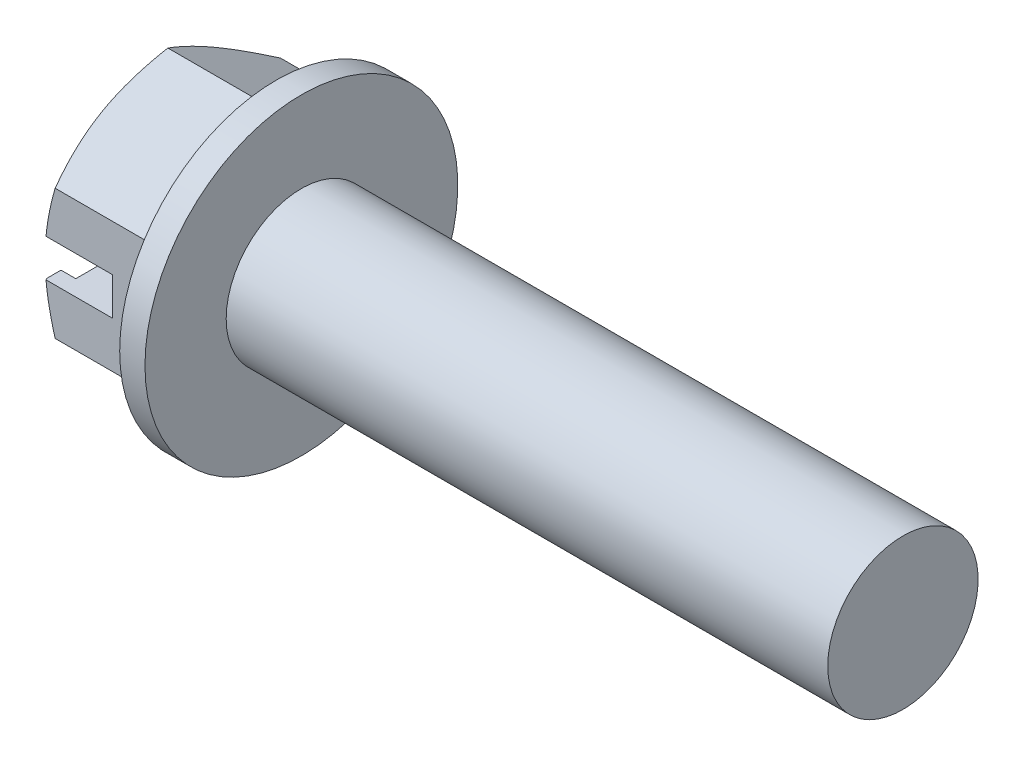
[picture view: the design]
ISO-10303-21;
HEADER;
FILE_DESCRIPTION(('STEP AP214'),'2;1');
FILE_NAME('part.step','',(''),(''),'','','');
FILE_SCHEMA(('AUTOMOTIVE_DESIGN { 1 0 10303 214 1 1 1 1 }'));
ENDSEC;
DATA;
#1=APPLICATION_CONTEXT('core data for automotive mechanical design processes');
#2=APPLICATION_PROTOCOL_DEFINITION('international standard','automotive_design',2000,#1);
#3=PRODUCT_CONTEXT('',#1,'mechanical');
#4=PRODUCT('Part','Part','',(#3));
#5=PRODUCT_RELATED_PRODUCT_CATEGORY('part','',(#4));
#6=PRODUCT_DEFINITION_FORMATION('','',#4);
#7=PRODUCT_DEFINITION_CONTEXT('part definition',#1,'design');
#8=PRODUCT_DEFINITION('design','',#6,#7);
#9=PRODUCT_DEFINITION_SHAPE('','',#8);
#10=(LENGTH_UNIT() NAMED_UNIT(*) SI_UNIT(.MILLI.,.METRE.));
#11=(NAMED_UNIT(*) PLANE_ANGLE_UNIT() SI_UNIT($,.RADIAN.));
#12=(NAMED_UNIT(*) SI_UNIT($,.STERADIAN.) SOLID_ANGLE_UNIT());
#13=UNCERTAINTY_MEASURE_WITH_UNIT(LENGTH_MEASURE(1.E-05),#10,'distance_accuracy_value','');
#14=(GEOMETRIC_REPRESENTATION_CONTEXT(3) GLOBAL_UNCERTAINTY_ASSIGNED_CONTEXT((#13)) GLOBAL_UNIT_ASSIGNED_CONTEXT((#10,
#11,#12)) REPRESENTATION_CONTEXT('',''));
#15=CARTESIAN_POINT('',(0.,0.,0.));
#16=DIRECTION('',(0.,0.,1.));
#17=DIRECTION('',(1.,0.,0.));
#18=AXIS2_PLACEMENT_3D('',#15,#16,#17);
#19=CARTESIAN_POINT('',(0.,0.,0.));
#20=DIRECTION('',(-1.,0.,0.));
#21=DIRECTION('',(0.,0.,1.));
#22=AXIS2_PLACEMENT_3D('',#19,#20,#21);
#23=PLANE('',#22);
#24=DIRECTION('',(0.,0.,-1.));
#25=VECTOR('',#24,1.);
#26=CARTESIAN_POINT('',(0.,-1.1938,0.));
#27=LINE('',#26,#25);
#28=CARTESIAN_POINT('',(0.,-1.1938,7.03685443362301));
#29=VERTEX_POINT('',#28);
#30=CARTESIAN_POINT('',(0.,-1.1938,6.13006336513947));
#31=VERTEX_POINT('',#30);
#32=EDGE_CURVE('E179',#29,#31,#27,.T.);
#33=ORIENTED_EDGE('',*,*,#32,.T.);
#34=CARTESIAN_POINT('',(0.,0.,0.));
#35=DIRECTION('',(1.,0.,0.));
#36=DIRECTION('',(0.,0.,-1.));
#37=AXIS2_PLACEMENT_3D('',#34,#35,#36);
#38=CIRCLE('',#37,6.245225);
#39=CARTESIAN_POINT('',(0.,-1.1938,-6.13006336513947));
#40=VERTEX_POINT('',#39);
#41=EDGE_CURVE('E164',#31,#40,#38,.T.);
#42=ORIENTED_EDGE('',*,*,#41,.T.);
#43=CARTESIAN_POINT('',(0.,-1.1938,-7.03685443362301));
#44=VERTEX_POINT('',#43);
#45=EDGE_CURVE('E176',#40,#44,#27,.T.);
#46=ORIENTED_EDGE('',*,*,#45,.T.);
#47=CARTESIAN_POINT('',(0.,0.,0.));
#48=DIRECTION('',(-1.,0.,0.));
#49=DIRECTION('',(0.,0.,1.));
#50=AXIS2_PLACEMENT_3D('',#47,#48,#49);
#51=CIRCLE('',#50,7.13739999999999);
#52=CARTESIAN_POINT('',(0.,-6.18116973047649,-3.5687000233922));
#53=VERTEX_POINT('',#52);
#54=EDGE_CURVE('E204',#44,#53,#51,.T.);
#55=ORIENTED_EDGE('',*,*,#54,.T.);
#56=CARTESIAN_POINT('',(0.,-6.18116973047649,3.5687000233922));
#57=VERTEX_POINT('',#56);
#58=EDGE_CURVE('E226',#53,#57,#51,.T.);
#59=ORIENTED_EDGE('',*,*,#58,.T.);
#60=EDGE_CURVE('E203',#57,#29,#51,.T.);
#61=ORIENTED_EDGE('',*,*,#60,.T.);
#62=EDGE_LOOP('',(#33,#42,#46,#55,#59,#61));
#63=FACE_BOUND('',#62,.T.);
#64=ADVANCED_FACE('F33',(#63),#23,.T.);
#65=DIRECTION('',(0.,0.,1.));
#66=VECTOR('',#65,1.);
#67=CARTESIAN_POINT('',(0.,1.1938,0.));
#68=LINE('',#67,#66);
#69=CARTESIAN_POINT('',(0.,1.1938,-7.03685443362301));
#70=VERTEX_POINT('',#69);
#71=CARTESIAN_POINT('',(0.,1.1938,-6.13006336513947));
#72=VERTEX_POINT('',#71);
#73=EDGE_CURVE('E168',#70,#72,#68,.T.);
#74=ORIENTED_EDGE('',*,*,#73,.T.);
#75=CARTESIAN_POINT('',(0.,1.1938,6.13006336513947));
#76=VERTEX_POINT('',#75);
#77=EDGE_CURVE('E157',#72,#76,#38,.T.);
#78=ORIENTED_EDGE('',*,*,#77,.T.);
#79=CARTESIAN_POINT('',(0.,1.1938,7.03685443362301));
#80=VERTEX_POINT('',#79);
#81=EDGE_CURVE('E177',#76,#80,#68,.T.);
#82=ORIENTED_EDGE('',*,*,#81,.T.);
#83=CARTESIAN_POINT('',(0.,6.18116973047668,3.56870002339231));
#84=VERTEX_POINT('',#83);
#85=EDGE_CURVE('E195',#80,#84,#51,.T.);
#86=ORIENTED_EDGE('',*,*,#85,.T.);
#87=CARTESIAN_POINT('',(0.,6.18116973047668,-3.56870002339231));
#88=VERTEX_POINT('',#87);
#89=EDGE_CURVE('E198',#84,#88,#51,.T.);
#90=ORIENTED_EDGE('',*,*,#89,.T.);
#91=EDGE_CURVE('E175',#88,#70,#51,.T.);
#92=ORIENTED_EDGE('',*,*,#91,.T.);
#93=EDGE_LOOP('',(#74,#78,#82,#86,#90,#92));
#94=FACE_BOUND('',#93,.T.);
#95=ADVANCED_FACE('F172',(#94),#23,.T.);
#96=CARTESIAN_POINT('',(4.2672,-1.1938,-8.24180138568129));
#97=DIRECTION('',(0.,1.,0.));
#98=DIRECTION('',(0.,0.,1.));
#99=AXIS2_PLACEMENT_3D('',#96,#97,#98);
#100=PLANE('',#99);
#101=ORIENTED_EDGE('',*,*,#45,.F.);
#102=DIRECTION('',(-1.,0.,0.));
#103=VECTOR('',#102,1.);
#104=CARTESIAN_POINT('',(0.936625,-1.1938,-6.13006336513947));
#105=LINE('',#104,#103);
#106=CARTESIAN_POINT('',(0.936625,-1.1938,-6.13006336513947));
#107=VERTEX_POINT('',#106);
#108=EDGE_CURVE('E338',#40,#107,#105,.F.);
#109=ORIENTED_EDGE('',*,*,#108,.T.);
#110=DIRECTION('',(0.,0.,-1.));
#111=VECTOR('',#110,1.);
#112=CARTESIAN_POINT('',(0.936625,-1.1938,-8.24180138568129));
#113=LINE('',#112,#111);
#114=CARTESIAN_POINT('',(0.936625,-1.1938,6.13006336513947));
#115=VERTEX_POINT('',#114);
#116=EDGE_CURVE('E189',#115,#107,#113,.T.);
#117=ORIENTED_EDGE('',*,*,#116,.F.);
#118=DIRECTION('',(-1.,0.,0.));
#119=VECTOR('',#118,1.);
#120=CARTESIAN_POINT('',(0.936625,-1.1938,6.13006336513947));
#121=LINE('',#120,#119);
#122=EDGE_CURVE('E287',#115,#31,#121,.T.);
#123=ORIENTED_EDGE('',*,*,#122,.T.);
#124=ORIENTED_EDGE('',*,*,#32,.F.);
#125=CARTESIAN_POINT('',(3.26043260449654,-1.1938,12.7287757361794));
#126=CARTESIAN_POINT('',(2.98204474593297,-1.1938,12.2444551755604));
#127=CARTESIAN_POINT('',(2.70374242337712,-1.1938,11.7600853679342));
#128=CARTESIAN_POINT('',(2.14746424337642,-1.1938,10.79121068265));
#129=CARTESIAN_POINT('',(1.8694883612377,-1.1938,10.3067058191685));
#130=CARTESIAN_POINT('',(1.31403888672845,-1.1938,9.33756042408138));
#131=CARTESIAN_POINT('',(1.03656519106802,-1.1938,8.85291995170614));
#132=CARTESIAN_POINT('',(0.620878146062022,-1.1938,8.12563576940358));
#133=CARTESIAN_POINT('',(0.482397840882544,-1.1938,7.88314465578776));
#134=CARTESIAN_POINT('',(0.205671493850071,-1.1938,7.39802631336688));
#135=CARTESIAN_POINT('',(0.0674254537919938,-1.1938,7.1553990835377));
#136=CARTESIAN_POINT('',(-0.208818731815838,-1.1938,6.66984777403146));
#137=CARTESIAN_POINT('',(-0.346816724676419,-1.1938,6.42692360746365));
#138=CARTESIAN_POINT('',(-0.62237324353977,-1.1938,5.94083477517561));
#139=CARTESIAN_POINT('',(-0.759931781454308,-1.1938,5.69767011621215));
#140=CARTESIAN_POINT('',(-1.03438897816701,-1.1938,5.21104351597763));
#141=CARTESIAN_POINT('',(-1.17128778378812,-1.1938,4.96758165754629));
#142=CARTESIAN_POINT('',(-1.4441587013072,-1.1938,4.48010659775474));
#143=CARTESIAN_POINT('',(-1.58013072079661,-1.1938,4.23609334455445));
#144=CARTESIAN_POINT('',(-1.7829941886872,-1.1938,3.86933760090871));
#145=CARTESIAN_POINT('',(-1.85046016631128,-1.1938,3.74691304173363));
#146=CARTESIAN_POINT('',(-1.98488099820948,-1.1938,3.50178681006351));
#147=CARTESIAN_POINT('',(-2.05183586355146,-1.1938,3.37908514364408));
#148=CARTESIAN_POINT('',(-2.18504184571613,-1.1938,3.13334895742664));
#149=CARTESIAN_POINT('',(-2.25129317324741,-1.1938,3.01031455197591));
#150=CARTESIAN_POINT('',(-2.38285615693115,-1.1938,2.7637302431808));
#151=CARTESIAN_POINT('',(-2.44816773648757,-1.1938,2.64018029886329));
#152=CARTESIAN_POINT('',(-2.57750557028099,-1.1938,2.39222873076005));
#153=CARTESIAN_POINT('',(-2.64153027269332,-1.1938,2.26782629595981));
#154=CARTESIAN_POINT('',(-2.76753475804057,-1.1938,2.01801587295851));
#155=CARTESIAN_POINT('',(-2.82951499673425,-1.1938,1.89260811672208));
#156=CARTESIAN_POINT('',(-2.92008574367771,-1.1938,1.7032539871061));
#157=CARTESIAN_POINT('',(-2.94989305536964,-1.1938,1.63989083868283));
#158=CARTESIAN_POINT('',(-3.0084424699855,-1.1938,1.51268002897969));
#159=CARTESIAN_POINT('',(-3.03718466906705,-1.1938,1.44883241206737));
#160=CARTESIAN_POINT('',(-3.09331464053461,-1.1938,1.32048035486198));
#161=CARTESIAN_POINT('',(-3.12070135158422,-1.1938,1.25597544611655));
#162=CARTESIAN_POINT('',(-3.17361063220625,-1.1938,1.126184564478));
#163=CARTESIAN_POINT('',(-3.19913261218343,-1.1938,1.06089835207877));
#164=CARTESIAN_POINT('',(-3.223470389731,-1.1938,0.995155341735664));
#165=B_SPLINE_CURVE_WITH_KNOTS('',3,(#125,#126,#127,#128,#129,#130,#131,#132,#133,#134,#135,
#136,#137,#138,#139,#140,#141,#142,#143,#144,#145,#146,#147,#148,#149,#150,#151,#152,#153,#154,
#155,#156,#157,#158,#159,#160,#161,#162,#163,#164),.UNSPECIFIED.,.F.,.F.,(4,2,2,2,2,2,2,2,2,2,2,
2,2,2,2,2,2,2,2,4),(0.,1.67588667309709,3.35163714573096,5.02699109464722,5.86473118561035,
6.70247766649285,7.54063032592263,8.3787600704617,9.21669377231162,10.0547098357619,
10.4740595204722,10.8934000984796,11.3126113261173,11.7318565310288,12.1515801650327,
12.5712095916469,12.7812741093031,12.9913196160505,13.2015270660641,13.4118006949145),.UNSPECIFIED.);
#166=CARTESIAN_POINT('',(0.0572435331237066,-1.1938,7.1374));
#167=VERTEX_POINT('',#166);
#168=EDGE_CURVE('E284',#167,#29,#165,.T.);
#169=ORIENTED_EDGE('',*,*,#168,.F.);
#170=DIRECTION('',(-1.,0.,0.));
#171=VECTOR('',#170,1.);
#172=CARTESIAN_POINT('',(7.493,-1.1938,7.1374));
#173=LINE('',#172,#171);
#174=CARTESIAN_POINT('',(4.2672,-1.1938,7.1374));
#175=VERTEX_POINT('',#174);
#176=EDGE_CURVE('E290',#175,#167,#173,.T.);
#177=ORIENTED_EDGE('',*,*,#176,.F.);
#178=DIRECTION('',(0.,0.,-1.));
#179=VECTOR('',#178,1.);
#180=CARTESIAN_POINT('',(4.2672,-1.1938,-8.24180138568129));
#181=LINE('',#180,#179);
#182=CARTESIAN_POINT('',(4.2672,-1.1938,-7.1374));
#183=VERTEX_POINT('',#182);
#184=EDGE_CURVE('E335',#175,#183,#181,.T.);
#185=ORIENTED_EDGE('',*,*,#184,.T.);
#186=DIRECTION('',(1.,0.,0.));
#187=VECTOR('',#186,1.);
#188=CARTESIAN_POINT('',(7.493,-1.1938,-7.1374));
#189=LINE('',#188,#187);
#190=CARTESIAN_POINT('',(0.0572435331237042,-1.1938,-7.1374));
#191=VERTEX_POINT('',#190);
#192=EDGE_CURVE('E291',#191,#183,#189,.T.);
#193=ORIENTED_EDGE('',*,*,#192,.F.);
#194=CARTESIAN_POINT('',(-3.223470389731,-1.1938,-0.995155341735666));
#195=CARTESIAN_POINT('',(-3.19924138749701,-1.1938,-1.0606056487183));
#196=CARTESIAN_POINT('',(-3.17383818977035,-1.1938,-1.1256031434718));
#197=CARTESIAN_POINT('',(-3.12118075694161,-1.1938,-1.25482287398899));
#198=CARTESIAN_POINT('',(-3.09392710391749,-1.1938,-1.31904534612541));
#199=CARTESIAN_POINT('',(-3.03807357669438,-1.1938,-1.44683300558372));
#200=CARTESIAN_POINT('',(-3.00947484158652,-1.1938,-1.51039869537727));
#201=CARTESIAN_POINT('',(-2.95121813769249,-1.1938,-1.63704855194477));
#202=CARTESIAN_POINT('',(-2.9215600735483,-1.1938,-1.7001326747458));
#203=CARTESIAN_POINT('',(-2.83143708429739,-1.1938,-1.88866522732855));
#204=CARTESIAN_POINT('',(-2.76976096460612,-1.1938,-2.01353350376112));
#205=CARTESIAN_POINT('',(-2.64436453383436,-1.1938,-2.26227255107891));
#206=CARTESIAN_POINT('',(-2.58064367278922,-1.1938,-2.38614304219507));
#207=CARTESIAN_POINT('',(-2.41929157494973,-1.1938,-2.69563915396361));
#208=CARTESIAN_POINT('',(-2.32080635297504,-1.1938,-2.88081872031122));
#209=CARTESIAN_POINT('',(-2.12205686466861,-1.1938,-3.25022110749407));
#210=CARTESIAN_POINT('',(-2.02179255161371,-1.1938,-3.43444390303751));
#211=CARTESIAN_POINT('',(-1.82013033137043,-1.1938,-3.80225262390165));
#212=CARTESIAN_POINT('',(-1.71873249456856,-1.1938,-3.98583858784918));
#213=CARTESIAN_POINT('',(-1.51516860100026,-1.1938,-4.35258440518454));
#214=CARTESIAN_POINT('',(-1.41300254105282,-1.1938,-4.53574425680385));
#215=CARTESIAN_POINT('',(-1.10543651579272,-1.1938,-5.0852656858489));
#216=CARTESIAN_POINT('',(-0.899238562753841,-1.1938,-5.45118036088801));
#217=CARTESIAN_POINT('',(-0.485698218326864,-1.1938,-6.18235721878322));
#218=CARTESIAN_POINT('',(-0.27835583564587,-1.1938,-6.54761940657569));
#219=CARTESIAN_POINT('',(0.205814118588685,-1.1938,-7.39864831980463));
#220=CARTESIAN_POINT('',(0.482912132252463,-1.1938,-7.88426115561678));
#221=CARTESIAN_POINT('',(1.03780984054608,-1.1938,-8.85508746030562));
#222=CARTESIAN_POINT('',(1.31560953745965,-1.1938,-9.34030092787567));
#223=CARTESIAN_POINT('',(1.87108240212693,-1.1938,-10.3094870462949));
#224=CARTESIAN_POINT('',(2.14875467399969,-1.1938,-10.7934602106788));
#225=CARTESIAN_POINT('',(2.70440087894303,-1.1938,-11.7612302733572));
#226=CARTESIAN_POINT('',(2.98237481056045,-1.1938,-12.2450271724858));
#227=CARTESIAN_POINT('',(3.26043260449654,-1.1938,-12.7287757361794));
#228=B_SPLINE_CURVE_WITH_KNOTS('',3,(#194,#195,#196,#197,#198,#199,#200,#201,#202,#203,#204,
#205,#206,#207,#208,#209,#210,#211,#212,#213,#214,#215,#216,#217,#218,#219,#220,#221,#222,#223,
#224,#225,#226,#227),.UNSPECIFIED.,.F.,.F.,(4,2,2,2,2,2,2,2,2,2,2,2,2,2,2,2,4),(0.,
0.209337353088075,0.418609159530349,0.627706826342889,0.836823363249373,1.2545977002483,
1.6724853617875,2.30168509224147,2.93090137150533,3.560078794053,4.1892588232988,
5.44929382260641,6.70931924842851,8.3866456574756,10.0639775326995,11.7378911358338,
13.4117967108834),.UNSPECIFIED.);
#229=EDGE_CURVE('E296',#44,#191,#228,.T.);
#230=ORIENTED_EDGE('',*,*,#229,.F.);
#231=EDGE_LOOP('',(#101,#109,#117,#123,#124,#169,#177,#185,#193,#230));
#232=FACE_BOUND('',#231,.T.);
#233=ADVANCED_FACE('F278',(#232),#100,.T.);
#234=CARTESIAN_POINT('',(4.2672,1.1938,8.24180138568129));
#235=DIRECTION('',(0.,-1.,0.));
#236=DIRECTION('',(0.,0.,-1.));
#237=AXIS2_PLACEMENT_3D('',#234,#235,#236);
#238=PLANE('',#237);
#239=ORIENTED_EDGE('',*,*,#81,.F.);
#240=DIRECTION('',(-1.,0.,0.));
#241=VECTOR('',#240,1.);
#242=CARTESIAN_POINT('',(0.936625,1.1938,6.13006336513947));
#243=LINE('',#242,#241);
#244=CARTESIAN_POINT('',(0.936625,1.1938,6.13006336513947));
#245=VERTEX_POINT('',#244);
#246=EDGE_CURVE('E11',#76,#245,#243,.F.);
#247=ORIENTED_EDGE('',*,*,#246,.T.);
#248=DIRECTION('',(0.,0.,1.));
#249=VECTOR('',#248,1.);
#250=CARTESIAN_POINT('',(0.936625,1.1938,8.24180138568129));
#251=LINE('',#250,#249);
#252=CARTESIAN_POINT('',(0.936625,1.1938,-6.13006336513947));
#253=VERTEX_POINT('',#252);
#254=EDGE_CURVE('E170',#253,#245,#251,.T.);
#255=ORIENTED_EDGE('',*,*,#254,.F.);
#256=DIRECTION('',(-1.,0.,0.));
#257=VECTOR('',#256,1.);
#258=CARTESIAN_POINT('',(0.936625,1.1938,-6.13006336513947));
#259=LINE('',#258,#257);
#260=EDGE_CURVE('E41',#253,#72,#259,.T.);
#261=ORIENTED_EDGE('',*,*,#260,.T.);
#262=ORIENTED_EDGE('',*,*,#73,.F.);
#263=CARTESIAN_POINT('',(3.26043260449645,1.1938,-12.7287757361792));
#264=CARTESIAN_POINT('',(2.98204474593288,1.1938,-12.2444551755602));
#265=CARTESIAN_POINT('',(2.70374242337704,1.1938,-11.760085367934));
#266=CARTESIAN_POINT('',(2.14746424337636,1.1938,-10.7912106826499));
#267=CARTESIAN_POINT('',(1.86948836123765,1.1938,-10.3067058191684));
#268=CARTESIAN_POINT('',(1.31403888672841,1.1938,-9.33756042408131));
#269=CARTESIAN_POINT('',(1.03656519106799,1.1938,-8.85291995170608));
#270=CARTESIAN_POINT('',(0.620878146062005,1.1938,-8.12563576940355));
#271=CARTESIAN_POINT('',(0.482397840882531,1.1938,-7.88314465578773));
#272=CARTESIAN_POINT('',(0.205671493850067,1.1938,-7.39802631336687));
#273=CARTESIAN_POINT('',(0.0674254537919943,1.1938,-7.1553990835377));
#274=CARTESIAN_POINT('',(-0.208818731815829,1.1938,-6.66984777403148));
#275=CARTESIAN_POINT('',(-0.346816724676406,1.1938,-6.42692360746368));
#276=CARTESIAN_POINT('',(-0.622373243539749,1.1938,-5.94083477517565));
#277=CARTESIAN_POINT('',(-0.759931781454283,1.1938,-5.69767011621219));
#278=CARTESIAN_POINT('',(-1.03438897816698,1.1938,-5.21104351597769));
#279=CARTESIAN_POINT('',(-1.17128778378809,1.1938,-4.96758165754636));
#280=CARTESIAN_POINT('',(-1.44415870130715,1.1938,-4.48010659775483));
#281=CARTESIAN_POINT('',(-1.58013072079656,1.1938,-4.23609334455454));
#282=CARTESIAN_POINT('',(-1.78299418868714,1.1938,-3.86933760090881));
#283=CARTESIAN_POINT('',(-1.85046016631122,1.1938,-3.74691304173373));
#284=CARTESIAN_POINT('',(-1.98488099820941,1.1938,-3.50178681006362));
#285=CARTESIAN_POINT('',(-2.05183586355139,1.1938,-3.37908514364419));
#286=CARTESIAN_POINT('',(-2.18504184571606,1.1938,-3.13334895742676));
#287=CARTESIAN_POINT('',(-2.25129317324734,1.1938,-3.01031455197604));
#288=CARTESIAN_POINT('',(-2.38285615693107,1.1938,-2.76373024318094));
#289=CARTESIAN_POINT('',(-2.4481677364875,1.1938,-2.64018029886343));
#290=CARTESIAN_POINT('',(-2.57750557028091,1.1938,-2.3922287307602));
#291=CARTESIAN_POINT('',(-2.64153027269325,1.1938,-2.26782629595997));
#292=CARTESIAN_POINT('',(-2.76753475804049,1.1938,-2.01801587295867));
#293=CARTESIAN_POINT('',(-2.82951499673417,1.1938,-1.89260811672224));
#294=CARTESIAN_POINT('',(-2.92008574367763,1.1938,-1.70325398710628));
#295=CARTESIAN_POINT('',(-2.94989305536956,1.1938,-1.639890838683));
#296=CARTESIAN_POINT('',(-3.00844246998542,1.1938,-1.51268002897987));
#297=CARTESIAN_POINT('',(-3.03718466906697,1.1938,-1.44883241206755));
#298=CARTESIAN_POINT('',(-3.09331464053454,1.1938,-1.32048035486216));
#299=CARTESIAN_POINT('',(-3.12070135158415,1.1938,-1.25597544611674));
#300=CARTESIAN_POINT('',(-3.17361063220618,1.1938,-1.12618456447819));
#301=CARTESIAN_POINT('',(-3.19913261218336,1.1938,-1.06089835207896));
#302=CARTESIAN_POINT('',(-3.22347038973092,1.1938,-0.995155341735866));
#303=B_SPLINE_CURVE_WITH_KNOTS('',3,(#263,#264,#265,#266,#267,#268,#269,#270,#271,#272,#273,
#274,#275,#276,#277,#278,#279,#280,#281,#282,#283,#284,#285,#286,#287,#288,#289,#290,#291,#292,
#293,#294,#295,#296,#297,#298,#299,#300,#301,#302),.UNSPECIFIED.,.F.,.F.,(4,2,2,2,2,2,2,2,2,2,2,
2,2,2,2,2,2,2,2,4),(0.,1.67588667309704,3.35163714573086,5.02699109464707,5.86473118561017,
6.70247766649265,7.5406303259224,8.37876007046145,9.21669377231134,10.0547098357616,
10.4740595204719,10.8934000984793,11.3126113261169,11.7318565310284,12.1515801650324,
12.5712095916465,12.7812741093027,12.9913196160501,13.2015270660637,13.4118006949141),.UNSPECIFIED.);
#304=CARTESIAN_POINT('',(0.0572435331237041,1.1938,-7.1374));
#305=VERTEX_POINT('',#304);
#306=EDGE_CURVE('E320',#305,#70,#303,.T.);
#307=ORIENTED_EDGE('',*,*,#306,.F.);
#308=DIRECTION('',(-1.,0.,0.));
#309=VECTOR('',#308,1.);
#310=CARTESIAN_POINT('',(7.493,1.1938,-7.1374));
#311=LINE('',#310,#309);
#312=CARTESIAN_POINT('',(4.2672,1.1938,-7.1374));
#313=VERTEX_POINT('',#312);
#314=EDGE_CURVE('E317',#313,#305,#311,.T.);
#315=ORIENTED_EDGE('',*,*,#314,.F.);
#316=DIRECTION('',(0.,0.,1.));
#317=VECTOR('',#316,1.);
#318=CARTESIAN_POINT('',(4.2672,1.1938,8.24180138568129));
#319=LINE('',#318,#317);
#320=CARTESIAN_POINT('',(4.2672,1.1938,7.1374));
#321=VERTEX_POINT('',#320);
#322=EDGE_CURVE('E332',#313,#321,#319,.T.);
#323=ORIENTED_EDGE('',*,*,#322,.T.);
#324=DIRECTION('',(1.,0.,0.));
#325=VECTOR('',#324,1.);
#326=CARTESIAN_POINT('',(7.493,1.1938,7.1374));
#327=LINE('',#326,#325);
#328=CARTESIAN_POINT('',(0.0572435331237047,1.1938,7.1374));
#329=VERTEX_POINT('',#328);
#330=EDGE_CURVE('E325',#329,#321,#327,.T.);
#331=ORIENTED_EDGE('',*,*,#330,.F.);
#332=CARTESIAN_POINT('',(-3.22347038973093,1.1938,0.995155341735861));
#333=CARTESIAN_POINT('',(-3.19924138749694,1.1938,1.0606056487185));
#334=CARTESIAN_POINT('',(-3.17383818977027,1.1938,1.125603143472));
#335=CARTESIAN_POINT('',(-3.12118075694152,1.1938,1.2548228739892));
#336=CARTESIAN_POINT('',(-3.09392710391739,1.1938,1.31904534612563));
#337=CARTESIAN_POINT('',(-3.03807357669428,1.1938,1.44683300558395));
#338=CARTESIAN_POINT('',(-3.00947484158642,1.1938,1.5103986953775));
#339=CARTESIAN_POINT('',(-2.95121813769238,1.1938,1.637048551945));
#340=CARTESIAN_POINT('',(-2.92156007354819,1.1938,1.70013267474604));
#341=CARTESIAN_POINT('',(-2.83143708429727,1.1938,1.88866522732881));
#342=CARTESIAN_POINT('',(-2.76976096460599,1.1938,2.01353350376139));
#343=CARTESIAN_POINT('',(-2.64436453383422,1.1938,2.26227255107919));
#344=CARTESIAN_POINT('',(-2.58064367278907,1.1938,2.38614304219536));
#345=CARTESIAN_POINT('',(-2.41929157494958,1.1938,2.6956391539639));
#346=CARTESIAN_POINT('',(-2.32080635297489,1.1938,2.88081872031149));
#347=CARTESIAN_POINT('',(-2.12205686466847,1.1938,3.25022110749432));
#348=CARTESIAN_POINT('',(-2.02179255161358,1.1938,3.43444390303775));
#349=CARTESIAN_POINT('',(-1.82013033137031,1.1938,3.80225262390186));
#350=CARTESIAN_POINT('',(-1.71873249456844,1.1938,3.98583858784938));
#351=CARTESIAN_POINT('',(-1.51516860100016,1.1938,4.35258440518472));
#352=CARTESIAN_POINT('',(-1.41300254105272,1.1938,4.53574425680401));
#353=CARTESIAN_POINT('',(-1.10543651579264,1.1938,5.08526568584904));
#354=CARTESIAN_POINT('',(-0.89923856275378,1.1938,5.45118036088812));
#355=CARTESIAN_POINT('',(-0.485698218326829,1.1938,6.18235721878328));
#356=CARTESIAN_POINT('',(-0.278355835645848,1.1938,6.54761940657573));
#357=CARTESIAN_POINT('',(0.205814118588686,1.1938,7.39864831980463));
#358=CARTESIAN_POINT('',(0.482912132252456,1.1938,7.88426115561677));
#359=CARTESIAN_POINT('',(1.03780984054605,1.1938,8.85508746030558));
#360=CARTESIAN_POINT('',(1.31560953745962,1.1938,9.34030092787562));
#361=CARTESIAN_POINT('',(1.87108240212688,1.1938,10.3094870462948));
#362=CARTESIAN_POINT('',(2.14875467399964,1.1938,10.7934602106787));
#363=CARTESIAN_POINT('',(2.70440087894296,1.1938,11.761230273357));
#364=CARTESIAN_POINT('',(2.98237481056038,1.1938,12.2450271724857));
#365=CARTESIAN_POINT('',(3.26043260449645,1.1938,12.7287757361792));
#366=B_SPLINE_CURVE_WITH_KNOTS('',3,(#332,#333,#334,#335,#336,#337,#338,#339,#340,#341,#342,
#343,#344,#345,#346,#347,#348,#349,#350,#351,#352,#353,#354,#355,#356,#357,#358,#359,#360,#361,
#362,#363,#364,#365),.UNSPECIFIED.,.F.,.F.,(4,2,2,2,2,2,2,2,2,2,2,2,2,2,2,2,4),(0.,
0.209337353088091,0.418609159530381,0.627706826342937,0.836823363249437,1.2545977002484,
1.67248536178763,2.30168509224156,2.93090137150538,3.56007879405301,4.18925882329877,
5.4492938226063,6.70931924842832,8.38664565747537,10.0639775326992,11.7378911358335,
13.411796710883),.UNSPECIFIED.);
#367=EDGE_CURVE('E193',#80,#329,#366,.T.);
#368=ORIENTED_EDGE('',*,*,#367,.F.);
#369=EDGE_LOOP('',(#239,#247,#255,#261,#262,#307,#315,#323,#331,#368));
#370=FACE_BOUND('',#369,.T.);
#371=ADVANCED_FACE('F167',(#370),#238,.T.);
#372=CARTESIAN_POINT('',(7.493,-4.12077982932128,7.13740000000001));
#373=DIRECTION('',(0.,0.,1.));
#374=DIRECTION('',(0.,-1.,0.));
#375=AXIS2_PLACEMENT_3D('',#372,#373,#374);
#376=PLANE('',#375);
#377=DIRECTION('',(0.,1.,0.));
#378=VECTOR('',#377,1.);
#379=CARTESIAN_POINT('',(4.2672,-4.12077982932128,7.13740000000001));
#380=LINE('',#379,#378);
#381=EDGE_CURVE('E293',#175,#321,#380,.T.);
#382=ORIENTED_EDGE('',*,*,#381,.F.);
#383=ORIENTED_EDGE('',*,*,#176,.T.);
#384=CARTESIAN_POINT('',(3.41544587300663,-10.9289347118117,7.13740000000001));
#385=CARTESIAN_POINT('',(3.26400695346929,-10.6155623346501,7.13740000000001));
#386=CARTESIAN_POINT('',(3.11407345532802,-10.3014490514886,7.13740000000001));
#387=CARTESIAN_POINT('',(2.81807755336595,-9.67134004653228,7.13740000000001));
#388=CARTESIAN_POINT('',(2.67201581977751,-9.35534401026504,7.13740000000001));
#389=CARTESIAN_POINT('',(2.38385424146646,-8.71936189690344,7.13740000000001));
#390=CARTESIAN_POINT('',(2.24178185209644,-8.39936333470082,7.13740000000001));
#391=CARTESIAN_POINT('',(1.96373939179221,-7.7567361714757,7.13740000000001));
#392=CARTESIAN_POINT('',(1.82776900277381,-7.43410770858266,7.13740000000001));
#393=CARTESIAN_POINT('',(1.56193891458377,-6.78170205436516,7.13740000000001));
#394=CARTESIAN_POINT('',(1.43217473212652,-6.45188572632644,7.13740000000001));
#395=CARTESIAN_POINT('',(1.18280932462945,-5.78836373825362,7.13740000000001));
#396=CARTESIAN_POINT('',(1.06320923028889,-5.45465765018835,7.13740000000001));
#397=CARTESIAN_POINT('',(0.837386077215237,-4.78350650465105,7.13740000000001));
#398=CARTESIAN_POINT('',(0.731134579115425,-4.44607112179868,7.13740000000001));
#399=CARTESIAN_POINT('',(0.535457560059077,-3.76641539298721,7.13740000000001));
#400=CARTESIAN_POINT('',(0.446026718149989,-3.42419659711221,7.1374));
#401=CARTESIAN_POINT('',(0.288339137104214,-2.73468312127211,7.1374));
#402=CARTESIAN_POINT('',(0.220088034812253,-2.38738711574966,7.1374));
#403=CARTESIAN_POINT('',(0.13701356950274,-1.86338701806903,7.1374));
#404=CARTESIAN_POINT('',(0.112537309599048,-1.68818947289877,7.1374));
#405=CARTESIAN_POINT('',(0.07050044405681,-1.33697297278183,7.1374));
#406=CARTESIAN_POINT('',(0.052939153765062,-1.16095410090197,7.1374));
#407=CARTESIAN_POINT('',(0.0252048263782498,-0.809449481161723,7.1374));
#408=CARTESIAN_POINT('',(0.0149859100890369,-0.633967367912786,7.1374));
#409=CARTESIAN_POINT('',(0.00199035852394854,-0.282727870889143,7.1374));
#410=CARTESIAN_POINT('',(-0.000786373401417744,-0.106970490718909,7.1374));
#411=CARTESIAN_POINT('',(0.0011686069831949,0.244453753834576,7.1374));
#412=CARTESIAN_POINT('',(0.00589821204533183,0.420120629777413,7.1374));
#413=CARTESIAN_POINT('',(0.0227482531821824,0.771101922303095,7.1374));
#414=CARTESIAN_POINT('',(0.0348690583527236,0.946416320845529,7.1374));
#415=CARTESIAN_POINT('',(0.072950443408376,1.37132382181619,7.1374));
#416=CARTESIAN_POINT('',(0.102614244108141,1.62059046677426,7.1374));
#417=CARTESIAN_POINT('',(0.175237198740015,2.11721366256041,7.1374));
#418=CARTESIAN_POINT('',(0.21819998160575,2.36456967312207,7.1374));
#419=CARTESIAN_POINT('',(0.315897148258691,2.85716752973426,7.1374));
#420=CARTESIAN_POINT('',(0.370642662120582,3.1024071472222,7.1374));
#421=CARTESIAN_POINT('',(0.490234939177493,3.59036322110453,7.1374));
#422=CARTESIAN_POINT('',(0.555080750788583,3.83307991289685,7.1374));
#423=CARTESIAN_POINT('',(0.6950173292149,4.32196822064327,7.1374));
#424=CARTESIAN_POINT('',(0.770320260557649,4.56807868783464,7.1374));
#425=CARTESIAN_POINT('',(0.92836652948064,5.05769822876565,7.1374));
#426=CARTESIAN_POINT('',(1.01110473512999,5.30120896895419,7.1374));
#427=CARTESIAN_POINT('',(1.18231251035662,5.78465193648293,7.1374));
#428=CARTESIAN_POINT('',(1.27074719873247,6.02459659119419,7.1374));
#429=CARTESIAN_POINT('',(1.45280721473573,6.50262425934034,7.1374));
#430=CARTESIAN_POINT('',(1.54643464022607,6.74070647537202,7.1374));
#431=CARTESIAN_POINT('',(1.64214475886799,6.97792376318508,7.1374));
#432=B_SPLINE_CURVE_WITH_KNOTS('',3,(#384,#385,#386,#387,#388,#389,#390,#391,#392,#393,#394,
#395,#396,#397,#398,#399,#400,#401,#402,#403,#404,#405,#406,#407,#408,#409,#410,#411,#412,#413,
#414,#415,#416,#417,#418,#419,#420,#421,#422,#423,#424,#425,#426,#427,#428,#429,#430,#431),
.UNSPECIFIED.,.F.,.F.,(4,2,2,2,2,2,2,2,2,2,2,2,2,2,2,2,2,2,2,2,2,2,2,4),(0.,1.0441518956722,
2.08848337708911,3.13879111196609,4.18904403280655,5.25219109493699,6.31545627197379,
7.37641628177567,8.43704010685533,9.49794596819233,10.0285279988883,10.559057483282,
11.0862423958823,11.6134204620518,12.1404505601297,12.6675069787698,13.4201640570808,
14.1730266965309,14.9266036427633,15.6801096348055,16.4520857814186,17.2235331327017,
17.9906382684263,18.7580556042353),.UNSPECIFIED.);
#433=CARTESIAN_POINT('',(0.637486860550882,-4.12077982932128,7.13740000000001));
#434=VERTEX_POINT('',#433);
#435=EDGE_CURVE('E238',#434,#167,#432,.T.);
#436=ORIENTED_EDGE('',*,*,#435,.F.);
#437=DIRECTION('',(-1.,0.,0.));
#438=VECTOR('',#437,1.);
#439=CARTESIAN_POINT('',(7.493,-4.12077982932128,7.13740000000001));
#440=LINE('',#439,#438);
#441=CARTESIAN_POINT('',(7.493,-4.12077982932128,7.13740000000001));
#442=VERTEX_POINT('',#441);
#443=EDGE_CURVE('E218',#442,#434,#440,.T.);
#444=ORIENTED_EDGE('',*,*,#443,.F.);
#445=DIRECTION('',(0.,1.,0.));
#446=VECTOR('',#445,1.);
#447=CARTESIAN_POINT('',(7.493,-4.12077982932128,7.13740000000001));
#448=LINE('',#447,#446);
#449=CARTESIAN_POINT('',(7.493,4.12077982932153,7.1374));
#450=VERTEX_POINT('',#449);
#451=EDGE_CURVE('E423',#442,#450,#448,.T.);
#452=ORIENTED_EDGE('',*,*,#451,.T.);
#453=DIRECTION('',(-1.,0.,0.));
#454=VECTOR('',#453,1.);
#455=CARTESIAN_POINT('',(7.493,4.12077982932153,7.1374));
#456=LINE('',#455,#454);
#457=CARTESIAN_POINT('',(0.637486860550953,4.12077982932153,7.1374));
#458=VERTEX_POINT('',#457);
#459=EDGE_CURVE('E380',#450,#458,#456,.T.);
#460=ORIENTED_EDGE('',*,*,#459,.T.);
#461=EDGE_CURVE('E222',#329,#458,#432,.T.);
#462=ORIENTED_EDGE('',*,*,#461,.F.);
#463=ORIENTED_EDGE('',*,*,#330,.T.);
#464=EDGE_LOOP('',(#382,#383,#436,#444,#452,#460,#462,#463));
#465=FACE_BOUND('',#464,.T.);
#466=ADVANCED_FACE('F260',(#465),#376,.T.);
#467=CARTESIAN_POINT('',(7.493,4.12077982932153,-7.1374));
#468=DIRECTION('',(0.,0.,-1.));
#469=DIRECTION('',(0.,1.,0.));
#470=AXIS2_PLACEMENT_3D('',#467,#468,#469);
#471=PLANE('',#470);
#472=CARTESIAN_POINT('',(3.41544587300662,-10.9289347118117,-7.1374));
#473=CARTESIAN_POINT('',(3.26400695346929,-10.6155623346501,-7.1374));
#474=CARTESIAN_POINT('',(3.11407345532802,-10.3014490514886,-7.1374));
#475=CARTESIAN_POINT('',(2.81807755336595,-9.67134004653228,-7.1374));
#476=CARTESIAN_POINT('',(2.6720158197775,-9.35534401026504,-7.1374));
#477=CARTESIAN_POINT('',(2.38385424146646,-8.71936189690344,-7.1374));
#478=CARTESIAN_POINT('',(2.24178185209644,-8.39936333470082,-7.1374));
#479=CARTESIAN_POINT('',(1.96373939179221,-7.75673617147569,-7.1374));
#480=CARTESIAN_POINT('',(1.82776900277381,-7.43410770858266,-7.1374));
#481=CARTESIAN_POINT('',(1.56193891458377,-6.78170205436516,-7.1374));
#482=CARTESIAN_POINT('',(1.43217473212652,-6.45188572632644,-7.1374));
#483=CARTESIAN_POINT('',(1.18280932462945,-5.78836373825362,-7.1374));
#484=CARTESIAN_POINT('',(1.06320923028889,-5.45465765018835,-7.1374));
#485=CARTESIAN_POINT('',(0.837386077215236,-4.78350650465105,-7.1374));
#486=CARTESIAN_POINT('',(0.731134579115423,-4.44607112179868,-7.1374));
#487=CARTESIAN_POINT('',(0.535457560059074,-3.76641539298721,-7.1374));
#488=CARTESIAN_POINT('',(0.446026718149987,-3.42419659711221,-7.1374));
#489=CARTESIAN_POINT('',(0.288339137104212,-2.73468312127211,-7.1374));
#490=CARTESIAN_POINT('',(0.220088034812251,-2.38738711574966,-7.1374));
#491=CARTESIAN_POINT('',(0.137013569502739,-1.86338701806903,-7.1374));
#492=CARTESIAN_POINT('',(0.112537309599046,-1.68818947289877,-7.1374));
#493=CARTESIAN_POINT('',(0.0705004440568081,-1.33697297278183,-7.1374));
#494=CARTESIAN_POINT('',(0.0529391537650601,-1.16095410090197,-7.1374));
#495=CARTESIAN_POINT('',(0.0252048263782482,-0.809449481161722,-7.1374));
#496=CARTESIAN_POINT('',(0.0149859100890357,-0.633967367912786,-7.1374));
#497=CARTESIAN_POINT('',(0.00199035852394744,-0.282727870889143,-7.1374));
#498=CARTESIAN_POINT('',(-0.000786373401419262,-0.106970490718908,-7.1374));
#499=CARTESIAN_POINT('',(0.00116860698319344,0.244453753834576,-7.1374));
#500=CARTESIAN_POINT('',(0.00589821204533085,0.420120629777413,-7.1374));
#501=CARTESIAN_POINT('',(0.0227482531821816,0.771101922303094,-7.1374));
#502=CARTESIAN_POINT('',(0.0348690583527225,0.946416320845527,-7.1374));
#503=CARTESIAN_POINT('',(0.0729504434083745,1.37132382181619,-7.1374));
#504=CARTESIAN_POINT('',(0.102614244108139,1.62059046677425,-7.1374));
#505=CARTESIAN_POINT('',(0.175237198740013,2.11721366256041,-7.1374));
#506=CARTESIAN_POINT('',(0.218199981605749,2.36456967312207,-7.1374));
#507=CARTESIAN_POINT('',(0.31589714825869,2.85716752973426,-7.1374));
#508=CARTESIAN_POINT('',(0.370642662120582,3.1024071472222,-7.1374));
#509=CARTESIAN_POINT('',(0.490234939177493,3.59036322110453,-7.1374));
#510=CARTESIAN_POINT('',(0.555080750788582,3.83307991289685,-7.1374));
#511=CARTESIAN_POINT('',(0.695017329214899,4.32196822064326,-7.1374));
#512=CARTESIAN_POINT('',(0.770320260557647,4.56807868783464,-7.1374));
#513=CARTESIAN_POINT('',(0.928366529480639,5.05769822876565,-7.1374));
#514=CARTESIAN_POINT('',(1.01110473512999,5.30120896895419,-7.1374));
#515=CARTESIAN_POINT('',(1.18231251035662,5.78465193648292,-7.1374));
#516=CARTESIAN_POINT('',(1.27074719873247,6.02459659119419,-7.1374));
#517=CARTESIAN_POINT('',(1.45280721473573,6.50262425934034,-7.1374));
#518=CARTESIAN_POINT('',(1.54643464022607,6.74070647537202,-7.1374));
#519=CARTESIAN_POINT('',(1.64214475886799,6.97792376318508,-7.1374));
#520=B_SPLINE_CURVE_WITH_KNOTS('',3,(#472,#473,#474,#475,#476,#477,#478,#479,#480,#481,#482,
#483,#484,#485,#486,#487,#488,#489,#490,#491,#492,#493,#494,#495,#496,#497,#498,#499,#500,#501,
#502,#503,#504,#505,#506,#507,#508,#509,#510,#511,#512,#513,#514,#515,#516,#517,#518,#519),
.UNSPECIFIED.,.F.,.F.,(4,2,2,2,2,2,2,2,2,2,2,2,2,2,2,2,2,2,2,2,2,2,2,4),(0.,1.0441518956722,
2.08848337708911,3.13879111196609,4.18904403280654,5.25219109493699,6.31545627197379,
7.37641628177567,8.43704010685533,9.49794596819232,10.0285279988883,10.559057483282,
11.0862423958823,11.6134204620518,12.1404505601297,12.6675069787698,13.4201640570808,
14.1730266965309,14.9266036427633,15.6801096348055,16.4520857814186,17.2235331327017,
17.9906382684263,18.7580556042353),.UNSPECIFIED.);
#521=CARTESIAN_POINT('',(0.63748686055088,-4.12077982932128,-7.1374));
#522=VERTEX_POINT('',#521);
#523=EDGE_CURVE('E352',#191,#522,#520,.F.);
#524=ORIENTED_EDGE('',*,*,#523,.F.);
#525=ORIENTED_EDGE('',*,*,#192,.T.);
#526=DIRECTION('',(0.,-1.,0.));
#527=VECTOR('',#526,1.);
#528=CARTESIAN_POINT('',(4.2672,4.12077982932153,-7.1374));
#529=LINE('',#528,#527);
#530=EDGE_CURVE('E186',#313,#183,#529,.T.);
#531=ORIENTED_EDGE('',*,*,#530,.F.);
#532=ORIENTED_EDGE('',*,*,#314,.T.);
#533=CARTESIAN_POINT('',(0.637486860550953,4.12077982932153,-7.1374));
#534=VERTEX_POINT('',#533);
#535=EDGE_CURVE('E407',#534,#305,#520,.F.);
#536=ORIENTED_EDGE('',*,*,#535,.F.);
#537=DIRECTION('',(-1.,0.,0.));
#538=VECTOR('',#537,1.);
#539=CARTESIAN_POINT('',(7.493,4.12077982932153,-7.1374));
#540=LINE('',#539,#538);
#541=CARTESIAN_POINT('',(7.493,4.12077982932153,-7.1374));
#542=VERTEX_POINT('',#541);
#543=EDGE_CURVE('E376',#542,#534,#540,.T.);
#544=ORIENTED_EDGE('',*,*,#543,.F.);
#545=DIRECTION('',(0.,-1.,0.));
#546=VECTOR('',#545,1.);
#547=CARTESIAN_POINT('',(7.493,4.12077982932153,-7.1374));
#548=LINE('',#547,#546);
#549=CARTESIAN_POINT('',(7.493,-4.12077982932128,-7.1374));
#550=VERTEX_POINT('',#549);
#551=EDGE_CURVE('E418',#542,#550,#548,.T.);
#552=ORIENTED_EDGE('',*,*,#551,.T.);
#553=DIRECTION('',(-1.,0.,0.));
#554=VECTOR('',#553,1.);
#555=CARTESIAN_POINT('',(7.493,-4.12077982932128,-7.1374));
#556=LINE('',#555,#554);
#557=EDGE_CURVE('E370',#550,#522,#556,.T.);
#558=ORIENTED_EDGE('',*,*,#557,.T.);
#559=EDGE_LOOP('',(#524,#525,#531,#532,#536,#544,#552,#558));
#560=FACE_BOUND('',#559,.T.);
#561=ADVANCED_FACE('F265',(#560),#471,.T.);
#562=CARTESIAN_POINT('',(0.,0.,0.));
#563=DIRECTION('',(1.,0.,0.));
#564=DIRECTION('',(0.,0.,-1.));
#565=AXIS2_PLACEMENT_3D('',#562,#563,#564);
#566=CONICAL_SURFACE('',#565,7.13739999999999,1.0471975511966);
#567=ORIENTED_EDGE('',*,*,#435,.T.);
#568=ORIENTED_EDGE('',*,*,#168,.T.);
#569=ORIENTED_EDGE('',*,*,#60,.F.);
#570=CARTESIAN_POINT('',(0.63755354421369,-8.24167512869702,-0.000200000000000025));
#571=CARTESIAN_POINT('',(0.585265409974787,-8.15109575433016,0.156688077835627));
#572=CARTESIAN_POINT('',(0.53535030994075,-8.06017865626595,0.314161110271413));
#573=CARTESIAN_POINT('',(0.440919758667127,-7.87760611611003,0.630386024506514));
#574=CARTESIAN_POINT('',(0.396406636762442,-7.78595037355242,0.78913842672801));
#575=CARTESIAN_POINT('',(0.271843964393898,-7.50951562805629,1.26793744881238));
#576=CARTESIAN_POINT('',(0.200994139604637,-7.32364544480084,1.58987404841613));
#577=CARTESIAN_POINT('',(0.117914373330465,-7.04549409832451,2.07164631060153));
#578=CARTESIAN_POINT('',(0.0942473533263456,-6.95404401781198,2.23004249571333));
#579=CARTESIAN_POINT('',(0.0545612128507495,-6.77073064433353,2.54755057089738));
#580=CARTESIAN_POINT('',(0.038541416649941,-6.67886738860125,2.70666239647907));
#581=CARTESIAN_POINT('',(0.014557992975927,-6.49498133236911,3.0251623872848));
#582=CARTESIAN_POINT('',(0.00658522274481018,-6.40295883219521,3.18455003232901));
#583=CARTESIAN_POINT('',(-0.00114174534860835,-6.2188339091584,3.50346375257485));
#584=CARTESIAN_POINT('',(-0.000896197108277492,-6.12673148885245,3.6629898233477));
#585=CARTESIAN_POINT('',(0.0110730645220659,-5.87440163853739,4.10003794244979));
#586=CARTESIAN_POINT('',(0.0311658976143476,-5.71425680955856,4.37741692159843));
#587=CARTESIAN_POINT('',(0.0948800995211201,-5.39503081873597,4.93033255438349));
#588=CARTESIAN_POINT('',(0.138523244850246,-5.23595077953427,5.20586726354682));
#589=CARTESIAN_POINT('',(0.247618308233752,-4.91608236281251,5.75989561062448));
#590=CARTESIAN_POINT('',(0.313532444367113,-4.75533434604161,6.03831934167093));
#591=CARTESIAN_POINT('',(0.463130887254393,-4.43623550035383,6.59101475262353));
#592=CARTESIAN_POINT('',(0.546780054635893,-4.2778805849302,6.86529351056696));
#593=CARTESIAN_POINT('',(0.637553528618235,-4.12066435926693,7.1376));
#594=B_SPLINE_CURVE_WITH_KNOTS('',3,(#570,#571,#572,#573,#574,#575,#576,#577,#578,#579,#580,
#581,#582,#583,#584,#585,#586,#587,#588,#589,#590,#591,#592,#593),.UNSPECIFIED.,.F.,.F.,(4,2,2,
2,2,2,2,2,2,2,2,4),(0.,0.565616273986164,1.1314755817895,2.26554548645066,2.81869147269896,
3.37178857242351,3.924256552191,4.47670746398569,5.43845616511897,6.40109570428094,
7.38508512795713,8.36714284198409),.UNSPECIFIED.);
#595=EDGE_CURVE('E250',#57,#434,#594,.T.);
#596=ORIENTED_EDGE('',*,*,#595,.T.);
#597=EDGE_LOOP('',(#567,#568,#569,#596));
#598=FACE_BOUND('',#597,.T.);
#599=ADVANCED_FACE('F256',(#598),#566,.T.);
#600=ORIENTED_EDGE('',*,*,#54,.F.);
#601=ORIENTED_EDGE('',*,*,#229,.T.);
#602=ORIENTED_EDGE('',*,*,#523,.T.);
#603=CARTESIAN_POINT('',(0.637553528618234,-4.12066435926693,-7.1376));
#604=CARTESIAN_POINT('',(0.585265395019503,-4.21124373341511,-6.98071192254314));
#605=CARTESIAN_POINT('',(0.535350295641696,-4.30216083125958,-6.82323889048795));
#606=CARTESIAN_POINT('',(0.440919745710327,-4.48473337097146,-6.50701397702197));
#607=CARTESIAN_POINT('',(0.396406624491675,-4.57638911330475,-6.348261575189));
#608=CARTESIAN_POINT('',(0.271843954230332,-4.85282385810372,-5.86946255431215));
#609=CARTESIAN_POINT('',(0.200994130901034,-5.03869404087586,-5.54752595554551));
#610=CARTESIAN_POINT('',(0.117914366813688,-5.31684538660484,-5.06575369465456));
#611=CARTESIAN_POINT('',(0.094247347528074,-5.40829546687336,-4.90735750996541));
#612=CARTESIAN_POINT('',(0.0545612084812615,-5.59160883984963,-4.58984943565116));
#613=CARTESIAN_POINT('',(0.0385414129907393,-5.68347209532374,-4.43073761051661));
#614=CARTESIAN_POINT('',(0.0145579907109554,-5.86735815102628,-4.11223762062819));
#615=CARTESIAN_POINT('',(0.0065852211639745,-5.95938065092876,-3.9528499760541));
#616=CARTESIAN_POINT('',(-0.00114174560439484,-6.14350557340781,-3.63393625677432));
#617=CARTESIAN_POINT('',(-0.000896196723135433,-6.23560799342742,-3.47441018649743));
#618=CARTESIAN_POINT('',(0.0110730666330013,-6.48793784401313,-3.03736206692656));
#619=CARTESIAN_POINT('',(0.0311659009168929,-6.64808267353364,-2.7599830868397));
#620=CARTESIAN_POINT('',(0.0948801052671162,-6.96730866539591,-2.20706745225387));
#621=CARTESIAN_POINT('',(0.138523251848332,-7.12638870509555,-1.93153274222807));
#622=CARTESIAN_POINT('',(0.247618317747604,-7.44625712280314,-1.37750439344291));
#623=CARTESIAN_POINT('',(0.313532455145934,-7.60700514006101,-1.099080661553));
#624=CARTESIAN_POINT('',(0.463130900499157,-7.92610398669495,-0.546385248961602));
#625=CARTESIAN_POINT('',(0.546780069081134,-8.08445890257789,-0.27210649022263));
#626=CARTESIAN_POINT('',(0.63755354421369,-8.24167512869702,0.00019999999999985));
#627=B_SPLINE_CURVE_WITH_KNOTS('',3,(#603,#604,#605,#606,#607,#608,#609,#610,#611,#612,#613,
#614,#615,#616,#617,#618,#619,#620,#621,#622,#623,#624,#625,#626),.UNSPECIFIED.,.F.,.F.,(4,2,2,
2,2,2,2,2,2,2,2,4),(0.,0.565616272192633,1.13147557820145,2.26554547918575,2.81869146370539,
3.37178856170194,3.92425653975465,4.47670744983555,5.43845615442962,6.40109569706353,
7.38508512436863,8.36714284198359),.UNSPECIFIED.);
#628=EDGE_CURVE('E351',#522,#53,#627,.T.);
#629=ORIENTED_EDGE('',*,*,#628,.T.);
#630=EDGE_LOOP('',(#600,#601,#602,#629));
#631=FACE_BOUND('',#630,.T.);
#632=ADVANCED_FACE('F349',(#631),#566,.T.);
#633=ORIENTED_EDGE('',*,*,#535,.T.);
#634=ORIENTED_EDGE('',*,*,#306,.T.);
#635=ORIENTED_EDGE('',*,*,#91,.F.);
#636=CARTESIAN_POINT('',(0.637553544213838,8.24167512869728,0.00020000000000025));
#637=CARTESIAN_POINT('',(0.585265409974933,8.15109575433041,-0.156688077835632));
#638=CARTESIAN_POINT('',(0.535350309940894,8.0601786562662,-0.314161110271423));
#639=CARTESIAN_POINT('',(0.440919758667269,7.87760611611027,-0.630386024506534));
#640=CARTESIAN_POINT('',(0.396406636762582,7.78595037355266,-0.789138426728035));
#641=CARTESIAN_POINT('',(0.271843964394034,7.50951562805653,-1.26793744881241));
#642=CARTESIAN_POINT('',(0.200994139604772,7.32364544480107,-1.58987404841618));
#643=CARTESIAN_POINT('',(0.117914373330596,7.04549409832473,-2.0716463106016));
#644=CARTESIAN_POINT('',(0.0942473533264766,6.95404401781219,-2.2300424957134));
#645=CARTESIAN_POINT('',(0.0545612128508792,6.77073064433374,-2.54755057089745));
#646=CARTESIAN_POINT('',(0.03854141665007,6.67886738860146,-2.70666239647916));
#647=CARTESIAN_POINT('',(0.0145579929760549,6.49498133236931,-3.02516238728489));
#648=CARTESIAN_POINT('',(0.0065852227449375,6.40295883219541,-3.1845500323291));
#649=CARTESIAN_POINT('',(-0.00114174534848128,6.21883390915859,-3.50346375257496));
#650=CARTESIAN_POINT('',(-0.000896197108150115,6.12673148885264,-3.66298982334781));
#651=CARTESIAN_POINT('',(0.0110730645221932,5.87440163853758,-4.10003794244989));
#652=CARTESIAN_POINT('',(0.0311658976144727,5.71425680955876,-4.37741692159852));
#653=CARTESIAN_POINT('',(0.0948800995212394,5.39503081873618,-4.93033255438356));
#654=CARTESIAN_POINT('',(0.138523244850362,5.23595077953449,-5.20586726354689));
#655=CARTESIAN_POINT('',(0.247618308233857,4.91608236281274,-5.75989561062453));
#656=CARTESIAN_POINT('',(0.313532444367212,4.75533434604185,-6.03831934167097));
#657=CARTESIAN_POINT('',(0.463130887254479,4.43623550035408,-6.59101475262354));
#658=CARTESIAN_POINT('',(0.546780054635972,4.27788058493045,-6.86529351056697));
#659=CARTESIAN_POINT('',(0.637553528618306,4.12066435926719,-7.1376));
#660=B_SPLINE_CURVE_WITH_KNOTS('',3,(#636,#637,#638,#639,#640,#641,#642,#643,#644,#645,#646,
#647,#648,#649,#650,#651,#652,#653,#654,#655,#656,#657,#658,#659),.UNSPECIFIED.,.F.,.F.,(4,2,2,
2,2,2,2,2,2,2,2,4),(0.,0.565616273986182,1.13147558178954,2.26554548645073,2.81869147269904,
3.37178857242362,3.92425655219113,4.47670746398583,5.43845616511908,6.40109570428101,
7.38508512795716,8.36714284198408),.UNSPECIFIED.);
#661=EDGE_CURVE('E223',#88,#534,#660,.T.);
#662=ORIENTED_EDGE('',*,*,#661,.T.);
#663=EDGE_LOOP('',(#633,#634,#635,#662));
#664=FACE_BOUND('',#663,.T.);
#665=ADVANCED_FACE('F410',(#664),#566,.T.);
#666=ORIENTED_EDGE('',*,*,#85,.F.);
#667=ORIENTED_EDGE('',*,*,#367,.T.);
#668=ORIENTED_EDGE('',*,*,#461,.T.);
#669=CARTESIAN_POINT('',(0.637553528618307,4.12066435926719,7.1376));
#670=CARTESIAN_POINT('',(0.585265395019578,4.21124373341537,6.98071192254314));
#671=CARTESIAN_POINT('',(0.535350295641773,4.30216083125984,6.82323889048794));
#672=CARTESIAN_POINT('',(0.440919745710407,4.48473337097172,6.50701397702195));
#673=CARTESIAN_POINT('',(0.396406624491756,4.57638911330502,6.34826157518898));
#674=CARTESIAN_POINT('',(0.27184395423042,4.85282385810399,5.86946255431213));
#675=CARTESIAN_POINT('',(0.200994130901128,5.03869404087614,5.54752595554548));
#676=CARTESIAN_POINT('',(0.117914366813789,5.31684538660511,5.06575369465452));
#677=CARTESIAN_POINT('',(0.0942473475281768,5.40829546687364,4.90735750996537));
#678=CARTESIAN_POINT('',(0.0545612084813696,5.59160883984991,4.58984943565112));
#679=CARTESIAN_POINT('',(0.0385414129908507,5.68347209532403,4.43073761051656));
#680=CARTESIAN_POINT('',(0.0145579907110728,5.86735815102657,4.11223762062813));
#681=CARTESIAN_POINT('',(0.00658522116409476,5.95938065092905,3.95284997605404));
#682=CARTESIAN_POINT('',(-0.00114174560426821,6.14350557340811,3.63393625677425));
#683=CARTESIAN_POINT('',(-0.000896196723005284,6.23560799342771,3.47441018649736));
#684=CARTESIAN_POINT('',(0.0110730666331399,6.48793784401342,3.0373620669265));
#685=CARTESIAN_POINT('',(0.0311659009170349,6.64808267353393,2.75998308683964));
#686=CARTESIAN_POINT('',(0.0948801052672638,6.96730866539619,2.20706745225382));
#687=CARTESIAN_POINT('',(0.138523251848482,7.12638870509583,1.93153274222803));
#688=CARTESIAN_POINT('',(0.247618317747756,7.44625712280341,1.37750439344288));
#689=CARTESIAN_POINT('',(0.313532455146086,7.60700514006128,1.09908066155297));
#690=CARTESIAN_POINT('',(0.463130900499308,7.92610398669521,0.54638524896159));
#691=CARTESIAN_POINT('',(0.546780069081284,8.08445890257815,0.272106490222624));
#692=CARTESIAN_POINT('',(0.637553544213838,8.24167512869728,-0.000199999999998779));
#693=B_SPLINE_CURVE_WITH_KNOTS('',3,(#669,#670,#671,#672,#673,#674,#675,#676,#677,#678,#679,
#680,#681,#682,#683,#684,#685,#686,#687,#688,#689,#690,#691,#692),.UNSPECIFIED.,.F.,.F.,(4,2,2,
2,2,2,2,2,2,2,2,4),(0.,0.565616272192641,1.13147557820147,2.26554547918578,2.81869146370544,
3.371788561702,3.92425653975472,4.47670744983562,5.43845615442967,6.40109569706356,
7.38508512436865,8.36714284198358),.UNSPECIFIED.);
#694=EDGE_CURVE('E210',#458,#84,#693,.T.);
#695=ORIENTED_EDGE('',*,*,#694,.T.);
#696=EDGE_LOOP('',(#666,#667,#668,#695));
#697=FACE_BOUND('',#696,.T.);
#698=ADVANCED_FACE('F220',(#697),#566,.T.);
#699=CARTESIAN_POINT('',(-25.4,0.,0.));
#700=DIRECTION('',(-1.,0.,0.));
#701=DIRECTION('',(0.,0.,1.));
#702=AXIS2_PLACEMENT_3D('',#699,#700,#701);
#703=CYLINDRICAL_SURFACE('',#702,4.76249999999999);
#704=CARTESIAN_POINT('',(47.1932,0.,0.));
#705=DIRECTION('',(-1.,0.,0.));
#706=DIRECTION('',(0.,0.,1.));
#707=AXIS2_PLACEMENT_3D('',#704,#705,#706);
#708=CIRCLE('',#707,4.76249999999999);
#709=CARTESIAN_POINT('',(47.1932,0.,4.76249999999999));
#710=VERTEX_POINT('',#709);
#711=EDGE_CURVE('E235',#710,#710,#708,.T.);
#712=ORIENTED_EDGE('',*,*,#711,.T.);
#713=EDGE_LOOP('',(#712));
#714=FACE_BOUND('',#713,.T.);
#715=CARTESIAN_POINT('',(9.0932,0.,0.));
#716=DIRECTION('',(-1.,0.,0.));
#717=DIRECTION('',(0.,0.,1.));
#718=AXIS2_PLACEMENT_3D('',#715,#716,#717);
#719=CIRCLE('',#718,4.76249999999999);
#720=CARTESIAN_POINT('',(9.0932,0.,4.76249999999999));
#721=VERTEX_POINT('',#720);
#722=EDGE_CURVE('E181',#721,#721,#719,.T.);
#723=ORIENTED_EDGE('',*,*,#722,.F.);
#724=EDGE_LOOP('',(#723));
#725=FACE_BOUND('',#724,.T.);
#726=ADVANCED_FACE('F35',(#714,#725),#703,.T.);
#727=CARTESIAN_POINT('',(9.0932,4.76249999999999,0.));
#728=DIRECTION('',(-1.,0.,0.));
#729=DIRECTION('',(0.,0.,1.));
#730=AXIS2_PLACEMENT_3D('',#727,#728,#729);
#731=PLANE('',#730);
#732=CARTESIAN_POINT('',(9.0932,0.,0.));
#733=DIRECTION('',(-1.,0.,0.));
#734=DIRECTION('',(0.,0.,1.));
#735=AXIS2_PLACEMENT_3D('',#732,#733,#734);
#736=CIRCLE('',#735,9.90599999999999);
#737=CARTESIAN_POINT('',(9.0932,0.,9.90599999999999));
#738=VERTEX_POINT('',#737);
#739=EDGE_CURVE('E618',#738,#738,#736,.T.);
#740=ORIENTED_EDGE('',*,*,#739,.F.);
#741=EDGE_LOOP('',(#740));
#742=FACE_BOUND('',#741,.T.);
#743=ORIENTED_EDGE('',*,*,#722,.T.);
#744=EDGE_LOOP('',(#743));
#745=FACE_BOUND('',#744,.T.);
#746=ADVANCED_FACE('F595',(#742,#745),#731,.F.);
#747=CARTESIAN_POINT('',(-25.4,0.,0.));
#748=DIRECTION('',(-1.,0.,0.));
#749=DIRECTION('',(0.,0.,1.));
#750=AXIS2_PLACEMENT_3D('',#747,#748,#749);
#751=CYLINDRICAL_SURFACE('',#750,9.90599999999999);
#752=ORIENTED_EDGE('',*,*,#739,.T.);
#753=EDGE_LOOP('',(#752));
#754=FACE_BOUND('',#753,.T.);
#755=CARTESIAN_POINT('',(7.493,0.,0.));
#756=DIRECTION('',(-1.,0.,0.));
#757=DIRECTION('',(0.,0.,1.));
#758=AXIS2_PLACEMENT_3D('',#755,#756,#757);
#759=CIRCLE('',#758,9.90599999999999);
#760=CARTESIAN_POINT('',(7.493,0.,9.90599999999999));
#761=VERTEX_POINT('',#760);
#762=EDGE_CURVE('E201',#761,#761,#759,.T.);
#763=ORIENTED_EDGE('',*,*,#762,.F.);
#764=EDGE_LOOP('',(#763));
#765=FACE_BOUND('',#764,.T.);
#766=ADVANCED_FACE('F580',(#754,#765),#751,.T.);
#767=CARTESIAN_POINT('',(7.493,8.24180138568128,0.));
#768=DIRECTION('',(-1.,0.,0.));
#769=DIRECTION('',(0.,0.,1.));
#770=AXIS2_PLACEMENT_3D('',#767,#768,#769);
#771=PLANE('',#770);
#772=ORIENTED_EDGE('',*,*,#762,.T.);
#773=EDGE_LOOP('',(#772));
#774=FACE_BOUND('',#773,.T.);
#775=ORIENTED_EDGE('',*,*,#451,.F.);
#776=DIRECTION('',(0.,0.50000000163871,0.866025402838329));
#777=VECTOR('',#776,1.);
#778=CARTESIAN_POINT('',(7.493,-8.24155965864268,0.));
#779=LINE('',#778,#777);
#780=CARTESIAN_POINT('',(7.493,-8.24155965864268,0.));
#781=VERTEX_POINT('',#780);
#782=EDGE_CURVE('E365',#781,#442,#779,.T.);
#783=ORIENTED_EDGE('',*,*,#782,.F.);
#784=DIRECTION('',(0.,-0.50000000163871,0.866025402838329));
#785=VECTOR('',#784,1.);
#786=CARTESIAN_POINT('',(7.493,-4.12077982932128,-7.1374));
#787=LINE('',#786,#785);
#788=EDGE_CURVE('E421',#550,#781,#787,.T.);
#789=ORIENTED_EDGE('',*,*,#788,.F.);
#790=ORIENTED_EDGE('',*,*,#551,.F.);
#791=DIRECTION('',(0.,-0.50000000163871,-0.866025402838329));
#792=VECTOR('',#791,1.);
#793=CARTESIAN_POINT('',(7.493,8.24155965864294,0.));
#794=LINE('',#793,#792);
#795=CARTESIAN_POINT('',(7.493,8.24155965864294,0.));
#796=VERTEX_POINT('',#795);
#797=EDGE_CURVE('E415',#796,#542,#794,.T.);
#798=ORIENTED_EDGE('',*,*,#797,.F.);
#799=DIRECTION('',(0.,0.50000000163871,-0.866025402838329));
#800=VECTOR('',#799,1.);
#801=CARTESIAN_POINT('',(7.493,4.12077982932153,7.1374));
#802=LINE('',#801,#800);
#803=EDGE_CURVE('E419',#450,#796,#802,.T.);
#804=ORIENTED_EDGE('',*,*,#803,.F.);
#805=EDGE_LOOP('',(#775,#783,#789,#790,#798,#804));
#806=FACE_BOUND('',#805,.T.);
#807=ADVANCED_FACE('F272',(#774,#806),#771,.T.);
#808=CARTESIAN_POINT('',(47.1932,4.76249999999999,0.));
#809=DIRECTION('',(1.,0.,0.));
#810=DIRECTION('',(0.,0.,-1.));
#811=AXIS2_PLACEMENT_3D('',#808,#809,#810);
#812=PLANE('',#811);
#813=ORIENTED_EDGE('',*,*,#711,.F.);
#814=EDGE_LOOP('',(#813));
#815=FACE_BOUND('',#814,.T.);
#816=ADVANCED_FACE('F269',(#815),#812,.T.);
#817=CARTESIAN_POINT('',(7.493,-8.24155965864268,0.));
#818=DIRECTION('',(0.,-0.866025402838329,0.50000000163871));
#819=DIRECTION('',(0.,-0.50000000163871,-0.866025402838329));
#820=AXIS2_PLACEMENT_3D('',#817,#818,#819);
#821=PLANE('',#820);
#822=DIRECTION('',(-1.,0.,0.));
#823=VECTOR('',#822,1.);
#824=CARTESIAN_POINT('',(7.493,-8.24155965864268,0.));
#825=LINE('',#824,#823);
#826=CARTESIAN_POINT('',(0.637486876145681,-8.24155965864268,0.));
#827=VERTEX_POINT('',#826);
#828=EDGE_CURVE('E368',#781,#827,#825,.T.);
#829=ORIENTED_EDGE('',*,*,#828,.F.);
#830=ORIENTED_EDGE('',*,*,#782,.T.);
#831=ORIENTED_EDGE('',*,*,#443,.T.);
#832=ORIENTED_EDGE('',*,*,#595,.F.);
#833=EDGE_CURVE('E249',#827,#57,#594,.T.);
#834=ORIENTED_EDGE('',*,*,#833,.F.);
#835=EDGE_LOOP('',(#829,#830,#831,#832,#834));
#836=FACE_BOUND('',#835,.T.);
#837=ADVANCED_FACE('F271',(#836),#821,.T.);
#838=CARTESIAN_POINT('',(7.493,-4.12077982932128,-7.1374));
#839=DIRECTION('',(0.,-0.866025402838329,-0.50000000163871));
#840=DIRECTION('',(0.,0.50000000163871,-0.866025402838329));
#841=AXIS2_PLACEMENT_3D('',#838,#839,#840);
#842=PLANE('',#841);
#843=ORIENTED_EDGE('',*,*,#557,.F.);
#844=ORIENTED_EDGE('',*,*,#788,.T.);
#845=ORIENTED_EDGE('',*,*,#828,.T.);
#846=EDGE_CURVE('E355',#53,#827,#627,.T.);
#847=ORIENTED_EDGE('',*,*,#846,.F.);
#848=ORIENTED_EDGE('',*,*,#628,.F.);
#849=EDGE_LOOP('',(#843,#844,#845,#847,#848));
#850=FACE_BOUND('',#849,.T.);
#851=ADVANCED_FACE('F397',(#850),#842,.T.);
#852=CARTESIAN_POINT('',(7.493,8.24155965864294,0.));
#853=DIRECTION('',(0.,0.866025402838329,-0.50000000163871));
#854=DIRECTION('',(0.,0.50000000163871,0.866025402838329));
#855=AXIS2_PLACEMENT_3D('',#852,#853,#854);
#856=PLANE('',#855);
#857=DIRECTION('',(-1.,0.,0.));
#858=VECTOR('',#857,1.);
#859=CARTESIAN_POINT('',(7.493,8.24155965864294,0.));
#860=LINE('',#859,#858);
#861=CARTESIAN_POINT('',(0.63748687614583,8.24155965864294,0.));
#862=VERTEX_POINT('',#861);
#863=EDGE_CURVE('E214',#796,#862,#860,.T.);
#864=ORIENTED_EDGE('',*,*,#863,.F.);
#865=ORIENTED_EDGE('',*,*,#797,.T.);
#866=ORIENTED_EDGE('',*,*,#543,.T.);
#867=ORIENTED_EDGE('',*,*,#661,.F.);
#868=EDGE_CURVE('E225',#862,#88,#660,.T.);
#869=ORIENTED_EDGE('',*,*,#868,.F.);
#870=EDGE_LOOP('',(#864,#865,#866,#867,#869));
#871=FACE_BOUND('',#870,.T.);
#872=ADVANCED_FACE('F394',(#871),#856,.T.);
#873=CARTESIAN_POINT('',(7.493,4.12077982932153,7.1374));
#874=DIRECTION('',(0.,0.866025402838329,0.50000000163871));
#875=DIRECTION('',(0.,-0.50000000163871,0.866025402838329));
#876=AXIS2_PLACEMENT_3D('',#873,#874,#875);
#877=PLANE('',#876);
#878=ORIENTED_EDGE('',*,*,#459,.F.);
#879=ORIENTED_EDGE('',*,*,#803,.T.);
#880=ORIENTED_EDGE('',*,*,#863,.T.);
#881=EDGE_CURVE('E208',#84,#862,#693,.T.);
#882=ORIENTED_EDGE('',*,*,#881,.F.);
#883=ORIENTED_EDGE('',*,*,#694,.F.);
#884=EDGE_LOOP('',(#878,#879,#880,#882,#883));
#885=FACE_BOUND('',#884,.T.);
#886=ADVANCED_FACE('F209',(#885),#877,.T.);
#887=ORIENTED_EDGE('',*,*,#58,.F.);
#888=ORIENTED_EDGE('',*,*,#846,.T.);
#889=ORIENTED_EDGE('',*,*,#833,.T.);
#890=EDGE_LOOP('',(#887,#888,#889));
#891=FACE_BOUND('',#890,.T.);
#892=ADVANCED_FACE('F359',(#891),#566,.T.);
#893=ORIENTED_EDGE('',*,*,#881,.T.);
#894=ORIENTED_EDGE('',*,*,#868,.T.);
#895=ORIENTED_EDGE('',*,*,#89,.F.);
#896=EDGE_LOOP('',(#893,#894,#895));
#897=FACE_BOUND('',#896,.T.);
#898=ADVANCED_FACE('F224',(#897),#566,.T.);
#899=CARTESIAN_POINT('',(4.2672,-1.1938,-8.24180138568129));
#900=DIRECTION('',(1.,0.,0.));
#901=DIRECTION('',(0.,0.,-1.));
#902=AXIS2_PLACEMENT_3D('',#899,#900,#901);
#903=PLANE('',#902);
#904=ORIENTED_EDGE('',*,*,#381,.T.);
#905=ORIENTED_EDGE('',*,*,#322,.F.);
#906=ORIENTED_EDGE('',*,*,#530,.T.);
#907=ORIENTED_EDGE('',*,*,#184,.F.);
#908=EDGE_LOOP('',(#904,#905,#906,#907));
#909=FACE_BOUND('',#908,.T.);
#910=ADVANCED_FACE('F431',(#909),#903,.F.);
#911=CARTESIAN_POINT('',(0.936625,0.,0.));
#912=DIRECTION('',(1.,0.,0.));
#913=DIRECTION('',(0.,0.,-1.));
#914=AXIS2_PLACEMENT_3D('',#911,#912,#913);
#915=PLANE('',#914);
#916=ORIENTED_EDGE('',*,*,#254,.T.);
#917=CARTESIAN_POINT('',(0.936625,0.,0.));
#918=DIRECTION('',(1.,0.,0.));
#919=DIRECTION('',(0.,0.,-1.));
#920=AXIS2_PLACEMENT_3D('',#917,#918,#919);
#921=CIRCLE('',#920,6.245225);
#922=EDGE_CURVE('E54',#253,#245,#921,.T.);
#923=ORIENTED_EDGE('',*,*,#922,.F.);
#924=EDGE_LOOP('',(#916,#923));
#925=FACE_BOUND('',#924,.T.);
#926=ADVANCED_FACE('F188',(#925),#915,.F.);
#927=CARTESIAN_POINT('',(0.936625,0.,0.));
#928=DIRECTION('',(-1.,0.,0.));
#929=DIRECTION('',(0.,0.,1.));
#930=AXIS2_PLACEMENT_3D('',#927,#928,#929);
#931=CYLINDRICAL_SURFACE('',#930,6.245225);
#932=ORIENTED_EDGE('',*,*,#77,.F.);
#933=ORIENTED_EDGE('',*,*,#260,.F.);
#934=ORIENTED_EDGE('',*,*,#922,.T.);
#935=ORIENTED_EDGE('',*,*,#246,.F.);
#936=EDGE_LOOP('',(#932,#933,#934,#935));
#937=FACE_BOUND('',#936,.T.);
#938=ADVANCED_FACE('F159',(#937),#931,.F.);
#939=ORIENTED_EDGE('',*,*,#41,.F.);
#940=ORIENTED_EDGE('',*,*,#122,.F.);
#941=EDGE_CURVE('E47',#115,#107,#921,.T.);
#942=ORIENTED_EDGE('',*,*,#941,.T.);
#943=ORIENTED_EDGE('',*,*,#108,.F.);
#944=EDGE_LOOP('',(#939,#940,#942,#943));
#945=FACE_BOUND('',#944,.T.);
#946=ADVANCED_FACE('F344',(#945),#931,.F.);
#947=ORIENTED_EDGE('',*,*,#116,.T.);
#948=ORIENTED_EDGE('',*,*,#941,.F.);
#949=EDGE_LOOP('',(#947,#948));
#950=FACE_BOUND('',#949,.T.);
#951=ADVANCED_FACE('F342',(#950),#915,.F.);
#952=CLOSED_SHELL('',(#64,#95,#233,#371,#466,#561,#599,#632,#665,#698,#726,#746,#766,#807,#816,
#837,#851,#872,#886,#892,#898,#910,#926,#938,#946,#951));
#953=MANIFOLD_SOLID_BREP('B2',#952);
#954=ADVANCED_BREP_SHAPE_REPRESENTATION('',(#18,#953),#14);
#955=SHAPE_DEFINITION_REPRESENTATION(#9,#954);
ENDSEC;
END-ISO-10303-21;
